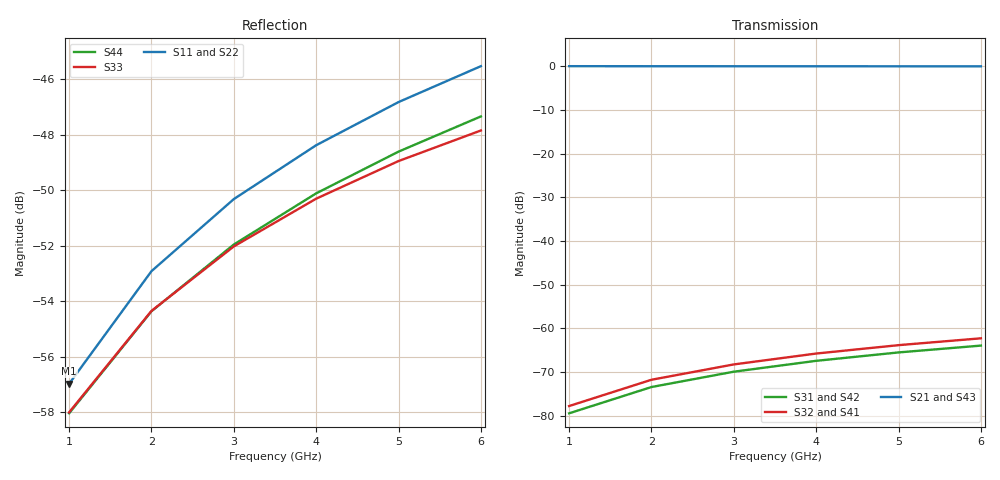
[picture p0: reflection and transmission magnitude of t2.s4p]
! Sonnet Data File
! From: em Version : 19.54.2026
! From Project: t2
! Data is De-embedded
! Data File Written: 11/09/2026 22:27:04
!< HDATE 11/09/2026 22:27:01
!< MDATE 11/09/2026 22:27:01
# GHZ S MA R 50.00000
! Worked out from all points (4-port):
!   6 points, 1 GHz to 6 GHz, reference 50 ohm
!   strongest paths, dB at 1 GHz, 2 GHz, 4 GHz, 5 GHz, 6 GHz:
!     S21: 0.0, 0.0, 0.0, 0.0, 0.0
!     S43: 0.0, 0.0, 0.0, 0.0, 0.0
!     S32: -77.7, -71.7, -65.7, -63.8, -62.3
!     S41: -77.8, -71.8, -65.8, -63.8, -62.3
!     S31: -79.4, -73.4, -67.4, -65.5, -63.9
!     S42: -79.4, -73.4, -67.4, -65.5, -63.9
!   lowest |S11| = -57.0 dB at 1 GHz (marker M1), VSWR 1.00, Z = 50 + j0.137 ohm
!   |S11| at or under -10 dB: start of sweep to end of sweep
1  0.001416 75.3  0.9986 -3.7  0.000107 -93.9  0.0001295 83.9
   0.9986 -3.7  0.00142 74.4  0.0001296 88.5  0.000107 -93.9
   0.000107 -93.9  0.0001296 88.5  0.001258 72.4  0.9986 -3.8
   0.0001295 83.9  0.000107 -93.9  0.9986 -3.8  0.001253 73.4
2  0.002259 81.6  0.9976 -7.5  0.0002138 -97.6  0.0002585 77.8
   0.9976 -7.5  0.00226 79.5  0.0002589 87.0  0.0002138 -97.8
   0.0002138 -97.6  0.0002589 87.0  0.001916 78.5  0.9976 -7.5
   0.0002585 77.8  0.0002138 -97.8  0.9976 -7.5  0.001913 81.2
3  0.003046 84.5  0.9968 -11.2  0.0003202 -101.4  0.000387 71.7
   0.9968 -11.2  0.003029 81.0  0.0003878 85.6  0.0003201 -101.6
   0.0003202 -101.4  0.0003878 85.6  0.002503 80.9  0.9967 -11.3
   0.000387 71.7  0.0003201 -101.6  0.9967 -11.3  0.002523 85.5
4  0.003808 85.6  0.996 -14.9  0.0004262 -105.1  0.0005149 65.7
   0.996 -14.9  0.003756 80.8  0.0005163 84.1  0.0004261 -105.4
   0.0004262 -105.1  0.0005163 84.1  0.003051 81.5  0.9959 -15.0
   0.0005149 65.7  0.0004261 -105.4  0.9959 -15.0  0.003119 88.0
5  0.004554 85.8  0.9952 -18.6  0.0005317 -108.8  0.0006422 59.6
   0.9952 -18.6  0.004447 79.6  0.000644 82.7  0.0005315 -109.2
   0.0005317 -108.8  0.000644 82.7  0.003566 81.0  0.9951 -18.8
   0.0006422 59.6  0.0005315 -109.2  0.9951 -18.8  0.003708 89.3
6  0.005285 85.3  0.9945 -22.3  0.0006366 -112.6  0.0007686 53.5
   0.9945 -22.3  0.005104 77.8  0.000771 81.3  0.0006364 -112.9
   0.0006366 -112.6  0.000771 81.3  0.004048 79.7  0.9944 -22.5
   0.0007686 53.5  0.0006364 -112.9  0.9944 -22.5  0.004291 89.8
